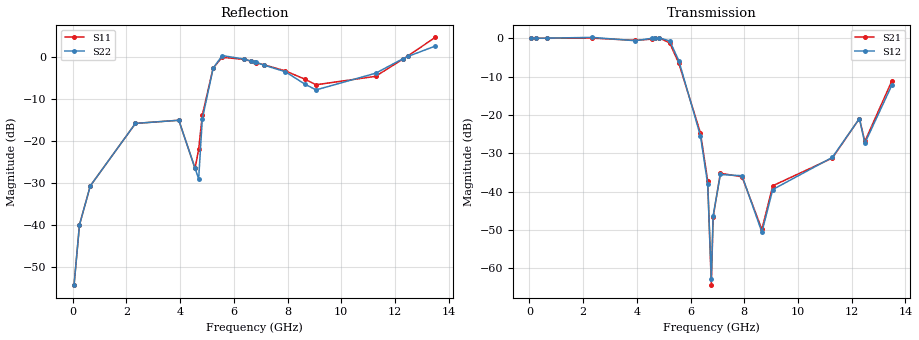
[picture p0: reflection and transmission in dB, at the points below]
! AVX THIN FILM OPERATION
! 0805 Size Low Pass Filter P/N  LP0805A3500AWTR
!	Network	Analyzer	HP8720ES.07.64:	Feb	"23,"	2000	Serial	No.	US39172382
!	Hewlett-Packard
!	2	Feb	2003	05:05:16
!	Frequency	S11	S21	S12	S22
#	HZ	S	DB	R	50
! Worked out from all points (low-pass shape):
!   201 points, 50 MHz to 13.5 GHz, reference 50 ohm
!   highest |S21| = 0.11 dB at 4.825 GHz (marker M1); lowest = -64.3 dB at 6.775 GHz (marker M2)
!   |S21| within 3 dB of the highest: start of sweep to 5.347 GHz
!   lowest |S11| = -54.3 dB at 50 MHz (marker M3), VSWR 1.00, Z = 50 - j0.193 ohm
!   |S11| at or under -10 dB: start of sweep to 4.919 GHz
!   |S22| runs from -54.3 to 2.6 dB; largest |S21 - S12| = 0.095
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5e7  -54.28 -92.8  0.01 -0.7  -0.01 -1.1  -54.28 94.2
2.5175e8  -39.94 -101.1  -0.02 -4.7  -0.02 -4.6  -39.94 -107.9
6.5525e8  -30.65 -127.1  -0.03 -12.0  -0.00 -12.1  -30.65 -121.5
2.3365e9  -15.78 147.7  0.01 -46.5  0.20 -45.5  -15.78 147.7
3.9505e9  -15.03 62.2  -0.58 -94.2  -0.67 -93.4  -15.03 70.5
4.55575e9  -26.49 -14.9  -0.25 -119.9  -0.04 -119.6  -26.49 21.5
4.69025e9  -21.93 -112.8  -0.08 -128.5  0.04 -129.1  -28.99 -143.7
4.82475e9  -13.86 -156.2  0.11 -138.9  0.13 -137.3  -14.76 -162.2
5.22825e9  -2.60 138.6  -1.27 175.5  -0.75 174.8  -2.67 142.5
5.5645e9  -0.04 93.9  -6.55 140.6  -5.88 133.9  0.37 96.4
6.3715e9  -0.53 27.7  -24.73 94.2  -25.49 89.7  -0.45 31.1
6.6405e9  -0.97 12.6  -37.21 85.9  -38.10 82.0  -0.95 16.3
6.775e9  -1.19 5.5  -64.34 143.7  -62.66 175.7  -1.13 9.0
6.84225e9  -1.34 2.0  -46.64 -108.0  -46.30 -115.2  -1.27 6.4
7.11125e9  -1.80 -11.0  -35.20 -108.3  -35.52 -113.0  -1.88 -6.0
7.91825e9  -3.28 -46.1  -36.13 -116.1  -35.84 -118.3  -3.48 -40.7
8.658e9  -5.29 -76.6  -49.84 -31.9  -50.53 -45.3  -6.48 -77.4
9.0615e9  -6.58 -96.0  -38.46 20.9  -39.44 10.5  -7.80 -101.8
1.128075e10  -4.57 129.4  -31.25 -115.9  -31.06 -116.9  -3.83 122.8
1.22895e10  -0.49 98.3  -20.94 168.8  -20.95 172.6  -0.40 92.0
1.249125e10  0.34 95.1  -26.90 163.5  -27.37 173.9  0.19 88.2
1.35e10  4.70 84.3  -11.12 147.5  -12.19 159.6  2.63 74.1
